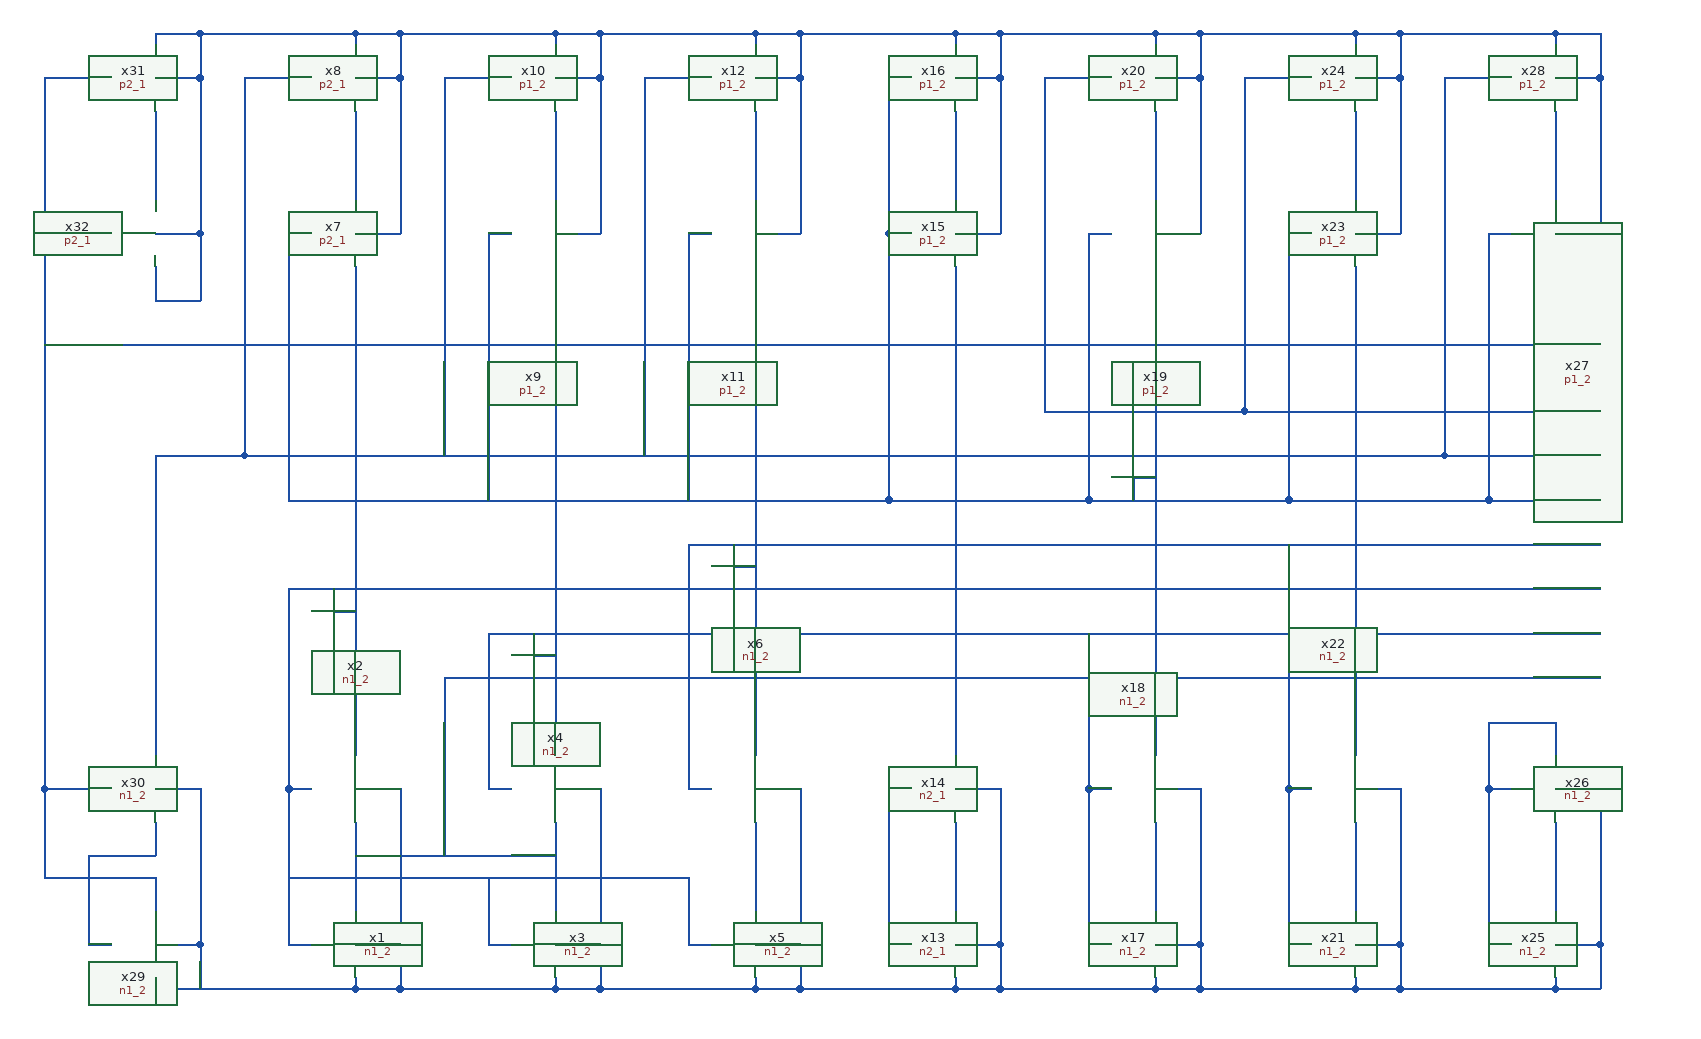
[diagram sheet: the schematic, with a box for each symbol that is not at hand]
v {xschem version=2.9.9 file_version=1.2 }
G {}
K {}
V {}
S {}
E {}
N 300 -170 300 -90 { lab=#net1}
N 240 -200 260 -200 { lab=#net2}
N 240 -200 240 -60 { lab=#net2}
N 240 -60 260 -60 { lab=#net2}
N 300 -200 340 -200 { lab=#net3}
N 340 -200 340 -20 { lab=#net3}
N 300 -20 340 -20 { lab=#net3}
N 300 -30 300 -20 { lab=#net3}
N 300 -60 340 -60 { lab=#net3}
N 480 -170 480 -90 { lab=#net1}
N 420 -200 440 -200 { lab=#net4}
N 420 -60 440 -60 { lab=#net2}
N 480 -200 520 -200 { lab=#net3}
N 520 -200 520 -20 { lab=#net3}
N 480 -20 520 -20 { lab=#net3}
N 480 -30 480 -20 { lab=#net3}
N 480 -60 520 -60 { lab=#net3}
N 420 -120 420 -60 { lab=#net2}
N 240 -120 420 -120 { lab=#net2}
N 300 -140 480 -140 { lab=#net1}
N 660 -170 660 -90 { lab=#net5}
N 600 -200 620 -200 { lab=#net6}
N 600 -60 620 -60 { lab=#net2}
N 660 -200 700 -200 { lab=#net3}
N 700 -200 700 -20 { lab=#net3}
N 660 -20 700 -20 { lab=#net3}
N 660 -30 660 -20 { lab=#net3}
N 660 -60 700 -60 { lab=#net3}
N 600 -120 600 -60 { lab=#net2}
N 240 -120 600 -120 { lab=#net2}
N 480 -260 480 -230 { lab=#net7}
N 660 -260 660 -230 { lab=#net8}
N 300 -260 300 -230 { lab=#net9}
N 300 -810 300 -730 { lab=#net10}
N 240 -700 260 -700 { lab=#net11}
N 300 -840 340 -840 { lab=#net12}
N 300 -700 340 -700 { lab=#net12}
N 340 -840 340 -700 { lab=#net12}
N 340 -880 340 -840 { lab=#net12}
N 300 -880 340 -880 { lab=#net12}
N 300 -880 300 -870 { lab=#net12}
N 480 -810 480 -730 { lab=#net13}
N 420 -700 440 -700 { lab=#net11}
N 480 -840 520 -840 { lab=#net12}
N 480 -700 520 -700 { lab=#net12}
N 520 -840 520 -700 { lab=#net12}
N 520 -880 520 -840 { lab=#net12}
N 480 -880 520 -880 { lab=#net12}
N 480 -880 480 -870 { lab=#net12}
N 300 -670 300 -260 { lab=#net9}
N 480 -670 480 -260 { lab=#net7}
N 660 -810 660 -730 { lab=#net14}
N 600 -700 620 -700 { lab=#net11}
N 660 -840 700 -840 { lab=#net12}
N 660 -700 700 -700 { lab=#net12}
N 700 -840 700 -700 { lab=#net12}
N 700 -880 700 -840 { lab=#net12}
N 660 -880 700 -880 { lab=#net12}
N 660 -880 660 -870 { lab=#net12}
N 340 -880 480 -880 { lab=#net12}
N 520 -880 660 -880 { lab=#net12}
N 660 -670 660 -260 { lab=#net8}
N 340 -20 480 -20 { lab=#net3}
N 520 -20 660 -20 { lab=#net3}
N 840 -170 840 -90 { lab=#net15}
N 780 -60 800 -60 { lab=#net16}
N 780 -200 780 -60 { lab=#net16}
N 780 -200 800 -200 { lab=#net16}
N 840 -200 880 -200 { lab=#net17}
N 880 -200 880 -60 { lab=#net17}
N 840 -60 880 -60 { lab=#net17}
N 880 -60 880 -20 { lab=#net17}
N 840 -20 880 -20 { lab=#net17}
N 840 -30 840 -20 { lab=#net17}
N 840 -810 840 -730 { lab=#net18}
N 780 -840 800 -840 { lab=#net11}
N 780 -700 800 -700 { lab=#net11}
N 840 -840 880 -840 { lab=#net12}
N 880 -880 880 -840 { lab=#net12}
N 840 -880 880 -880 { lab=#net12}
N 840 -880 840 -870 { lab=#net12}
N 840 -700 880 -700 { lab=#net12}
N 880 -840 880 -700 { lab=#net12}
N 1020 -170 1020 -90 { lab=#net19}
N 960 -60 980 -60 { lab=#net20}
N 960 -200 960 -60 { lab=#net20}
N 960 -200 980 -200 { lab=#net20}
N 1020 -200 1060 -200 { lab=#net21}
N 1060 -200 1060 -60 { lab=#net21}
N 1020 -60 1060 -60 { lab=#net21}
N 1060 -60 1060 -20 { lab=#net21}
N 1020 -20 1060 -20 { lab=#net21}
N 1020 -30 1020 -20 { lab=#net21}
N 1020 -810 1020 -730 { lab=#net22}
N 960 -700 980 -700 { lab=#net11}
N 1020 -840 1060 -840 { lab=#net12}
N 1060 -880 1060 -840 { lab=#net12}
N 1020 -880 1060 -880 { lab=#net12}
N 1020 -880 1020 -870 { lab=#net12}
N 1020 -700 1060 -700 { lab=#net12}
N 1060 -840 1060 -700 { lab=#net12}
N 1200 -170 1200 -90 { lab=#net23}
N 1140 -60 1160 -60 { lab=#net24}
N 1140 -200 1140 -60 { lab=#net24}
N 1140 -200 1160 -200 { lab=#net24}
N 1200 -200 1240 -200 { lab=#net25}
N 1240 -200 1240 -60 { lab=#net25}
N 1200 -60 1240 -60 { lab=#net25}
N 1240 -60 1240 -20 { lab=#net25}
N 1200 -20 1240 -20 { lab=#net25}
N 1200 -30 1200 -20 { lab=#net25}
N 1200 -810 1200 -730 { lab=#net26}
N 1140 -700 1160 -700 { lab=#net11}
N 1200 -840 1240 -840 { lab=#net12}
N 1240 -880 1240 -840 { lab=#net12}
N 1200 -880 1240 -880 { lab=#net12}
N 1200 -880 1200 -870 { lab=#net12}
N 1200 -700 1240 -700 { lab=#net12}
N 1240 -840 1240 -700 { lab=#net12}
N 840 -670 840 -230 { lab=#net27}
N 1020 -670 1020 -230 { lab=#net11}
N 1200 -670 1200 -230 { lab=#net28}
N 1380 -170 1380 -90 { lab=#net29}
N 1320 -60 1340 -60 { lab=#net30}
N 1320 -200 1320 -60 { lab=#net30}
N 1320 -200 1340 -200 { lab=#net30}
N 1380 -200 1420 -200 { lab=#net31}
N 1420 -200 1420 -60 { lab=#net31}
N 1380 -60 1420 -60 { lab=#net31}
N 1420 -60 1420 -20 { lab=#net31}
N 1380 -20 1420 -20 { lab=#net31}
N 1380 -30 1380 -20 { lab=#net31}
N 1380 -810 1380 -730 { lab=#net32}
N 1320 -700 1340 -700 { lab=#net11}
N 1380 -840 1420 -840 { lab=#net12}
N 1420 -880 1420 -840 { lab=#net12}
N 1380 -880 1420 -880 { lab=#net12}
N 1380 -880 1380 -870 { lab=#net12}
N 1380 -700 1420 -700 { lab=#net12}
N 1420 -840 1420 -700 { lab=#net12}
N 1380 -260 1380 -230 { lab=#net33}
N 780 -840 780 -780 { lab=#net11}
N 780 -780 780 -700 { lab=#net11}
N 200 -840 260 -840 { lab=#net34}
N 200 -840 200 -500 { lab=#net34}
N 920 -840 980 -840 { lab=#net35}
N 920 -840 920 -540 { lab=#net35}
N 1100 -840 1160 -840 { lab=#net35}
N 920 -540 1100 -540 { lab=#net35}
N 1100 -840 1100 -540 { lab=#net35}
N 780 -700 780 -460 { lab=#net11}
N 780 -460 960 -460 { lab=#net11}
N 960 -700 960 -460 { lab=#net11}
N 960 -460 1140 -460 { lab=#net11}
N 1140 -700 1140 -460 { lab=#net11}
N 1140 -460 1320 -460 { lab=#net11}
N 1320 -700 1320 -460 { lab=#net11}
N 1000 -480 1020 -480 { lab=#net11}
N 1000 -480 1000 -460 { lab=#net11}
N 1280 -840 1340 -840 { lab=#net34}
N 1280 -840 1280 -500 { lab=#net34}
N 200 -500 1280 -500 { lab=#net34}
N 240 -700 240 -460 { lab=#net11}
N 240 -460 780 -460 { lab=#net11}
N 420 -700 420 -460 { lab=#net11}
N 600 -700 600 -460 { lab=#net11}
N 560 -840 620 -840 { lab=#net34}
N 560 -840 560 -500 { lab=#net34}
N 380 -840 440 -840 { lab=#net34}
N 380 -840 380 -500 { lab=#net34}
N 700 -880 840 -880 { lab=#net12}
N 880 -880 1020 -880 { lab=#net12}
N 1060 -880 1200 -880 { lab=#net12}
N 1240 -880 1380 -880 { lab=#net12}
N 1100 -540 1420 -540 { lab=#net35}
N 1280 -500 1420 -500 { lab=#net34}
N 1320 -460 1420 -460 { lab=#net11}
N 120 -200 160 -200 { lab=#net36}
N 160 -200 160 -60 { lab=#net36}
N 120 -60 160 -60 { lab=#net36}
N 120 -840 160 -840 {}
N 160 -880 160 -840 {}
N 160 -880 300 -880 {}
N 120 -880 160 -880 {}
N 120 -880 120 -870 {}
N 120 -810 120 -730 {}
N 160 -840 160 -700 {}
N 120 -700 160 -700 {}
N 120 -670 120 -640 {}
N 120 -640 160 -640 {}
N 160 -700 160 -640 {}
N 60 -700 80 -700 {}
N 20 -840 20 -700 {}
N 120 -120 120 -90 {}
N 120 -170 120 -140 {}
N 60 -140 60 -60 {}
N 20 -200 20 -120 {}
N 120 -500 200 -500 {}
N 120 -500 120 -230 {}
N 60 -60 80 -60 {}
N 60 -140 120 -140 {}
N 20 -120 120 -120 {}
N 20 -200 80 -200 {}
N 20 -700 20 -200 {}
N 20 -700 60 -700 {}
N 20 -840 80 -840 {}
N 20 -600 1420 -600 {}
N 120 -30 120 -20 {}
N 120 -20 300 -20 {}
N 160 -60 160 -20 {}
N 380 -300 380 -140 {}
N 380 -300 1420 -300 {}
N 1320 -260 1380 -260 {}
N 1320 -260 1320 -200 {}
N 420 -340 420 -200 {}
N 240 -380 240 -200 {}
N 420 -340 1420 -340 {}
N 240 -380 1420 -380 {}
N 600 -420 600 -200 {}
N 600 -420 1420 -420 {}
N 280 -380 280 -360 {}
N 280 -360 300 -360 {}
N 460 -340 460 -320 {}
N 460 -320 480 -320 {}
N 640 -420 640 -400 {}
N 640 -400 660 -400 {}
N 700 -20 840 -20 {}
N 880 -20 1020 -20 {}
N 1060 -20 1200 -20 {}
N 1240 -20 1380 -20 {}
N 960 -340 960 -200 {}
N 1140 -420 1140 -200 {}
C {n1_2.sym} 280 -60 0 0 {name=x1}
C {n1_2.sym} 280 -200 0 0 {name=x2}
C {n1_2.sym} 460 -60 0 0 {name=x3}
C {n1_2.sym} 460 -200 0 0 {name=x4}
C {n1_2.sym} 640 -60 0 0 {name=x5}
C {n1_2.sym} 640 -200 0 0 {name=x6}
C {p2_1.sym} 280 -700 0 0 {name=x7}
C {p2_1.sym} 280 -840 0 0 {name=x8}
C {p1_2.sym} 460 -700 0 0 {name=x9}
C {p1_2.sym} 460 -840 0 0 {name=x10}
C {p1_2.sym} 640 -700 0 0 {name=x11}
C {p1_2.sym} 640 -840 0 0 {name=x12}
C {n2_1.sym} 820 -60 0 0 {name=x13}
C {n2_1.sym} 820 -200 0 0 {name=x14}
C {p1_2.sym} 820 -700 0 0 {name=x15}
C {p1_2.sym} 820 -840 0 0 {name=x16}
C {n1_2.sym} 1000 -60 0 0 {name=x17}
C {n1_2.sym} 1000 -200 0 0 {name=x18}
C {p1_2.sym} 1000 -700 0 0 {name=x19}
C {p1_2.sym} 1000 -840 0 0 {name=x20}
C {n1_2.sym} 1180 -60 0 0 {name=x21}
C {n1_2.sym} 1180 -200 0 0 {name=x22}
C {p1_2.sym} 1180 -700 0 0 {name=x23}
C {p1_2.sym} 1180 -840 0 0 {name=x24}
C {n1_2.sym} 1360 -60 0 0 {name=x25}
C {n1_2.sym} 1360 -200 0 0 {name=x26}
C {p1_2.sym} 1360 -700 0 0 {name=x27}
C {p1_2.sym} 1360 -840 0 0 {name=x28}
C {n1_2.sym} 100 -60 0 0 {name=x29}
C {n1_2.sym} 100 -200 0 0 {name=x30}
C {p2_1.sym} 100 -840 0 0 {name=x31}
C {p2_1.sym} 100 -700 0 0 {name=x32}
